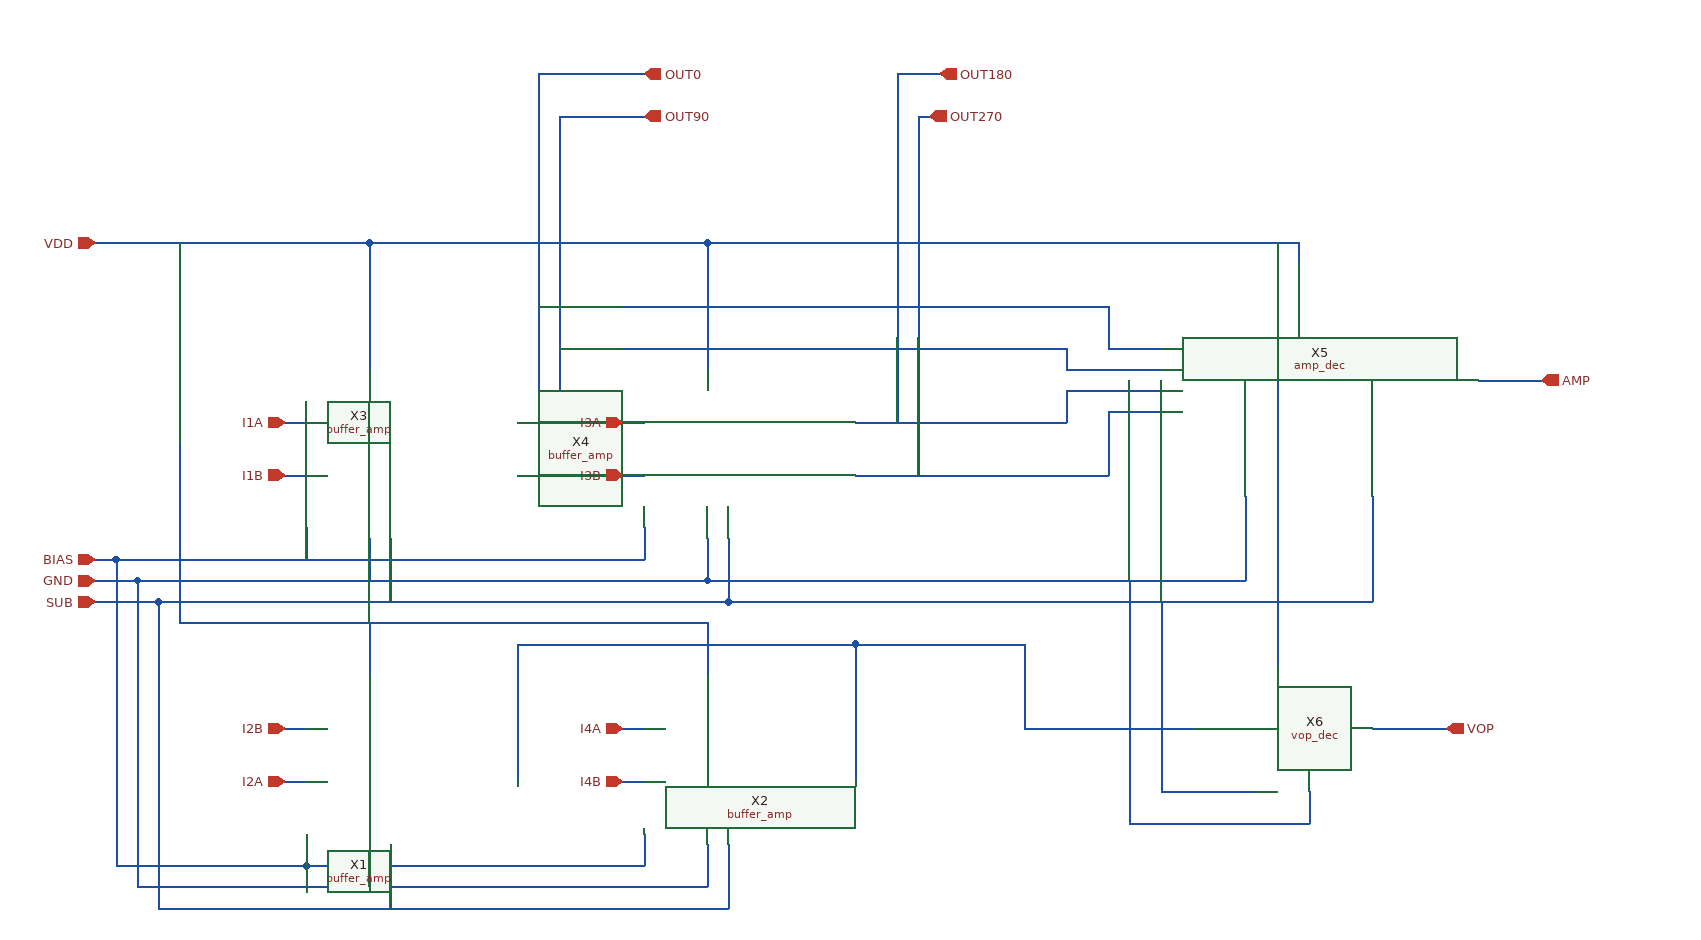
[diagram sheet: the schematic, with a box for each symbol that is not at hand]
v {xschem version=3.0.0 file_version=1.2 }
G {}
K {}
V {}
S {}
E {}
N 400 -280 400 -220 {
lab=SUB}
N -80 -220 400 -220 {
lab=SUB}
N 380 -280 380 -240 {
lab=GND}
N -80 -240 380 -240 {
lab=GND}
N 320 -290 320 -260 {
lab=BIAS}
N -70 -260 320 -260 {
lab=BIAS}
N -200 -260 -190 -260 {
lab=BIAS}
N -0 -290 -0 -260 {
lab=BIAS}
N 60 -280 60 -240 {
lab=GND}
N 80 -280 80 -220 {
lab=SUB}
N 400 10 400 70 {
lab=SUB}
N 380 10 380 50 {
lab=GND}
N 320 0 320 30 {
lab=BIAS}
N 0 0 0 30 {
lab=BIAS}
N 60 10 60 50 {
lab=GND}
N 80 10 80 70 {
lab=SUB}
N -180 -260 -180 20 {
lab=BIAS}
N -180 20 -180 30 {
lab=BIAS}
N -160 -240 -160 50 {
lab=GND}
N -140 -220 -140 70 {
lab=SUB}
N -60 30 0 30 {
lab=BIAS}
N 0 30 320 30 {
lab=BIAS}
N -40 50 380 50 {
lab=GND}
N -20 70 400 70 {
lab=SUB}
N -20 -340 -0 -340 {
lab=I1B}
N -20 -390 0 -390 {
lab=I1A}
N 300 -390 320 -390 {
lab=I3A}
N 300 -340 320 -340 {
lab=I3B}
N -180 30 -60 30 {
lab=BIAS}
N -160 50 -40 50 {
lab=GND}
N -140 70 -20 70 {
lab=SUB}
N -140 -220 -80 -220 {
lab=SUB}
N -160 -240 -80 -240 {
lab=GND}
N -180 -260 -70 -260 {
lab=BIAS}
N -190 -260 -180 -260 {
lab=BIAS}
N -200 -240 -160 -240 {
lab=GND}
N -200 -220 -140 -220 {
lab=SUB}
N -20 -100 0 -100 {
lab=I2B}
N -20 -50 -0 -50 {
lab=I2A}
N 200 -100 200 -50 {
lab=#net1}
N 300 -100 320 -100 {
lab=I4A}
N 300 -50 320 -50 {
lab=I4B}
N 520 -100 520 -50 {
lab=#net1}
N 60 -560 380 -560 {
lab=VDD}
N -200 -560 60 -560 {
lab=VDD}
N 200 -130 200 -100 {
lab=#net1}
N 380 -200 380 -150 {
lab=VDD}
N -120 -200 380 -200 {
lab=VDD}
N -120 -440 -120 -200 {
lab=VDD}
N 60 -200 60 -150 {
lab=VDD}
N 200 -180 200 -130 {
lab=#net1}
N 200 -180 520 -180 {
lab=#net1}
N 520 -180 520 -100 {
lab=#net1}
N 520 -180 680 -180 {
lab=#net1}
N 520 -340 680 -340 {
lab=OUT270}
N 520 -390 680 -390 {
lab=OUT180}
N 200 -390 220 -390 {
lab=OUT0}
N 220 -600 220 -390 {
lab=OUT0}
N 200 -340 240 -340 {
lab=OUT90}
N 240 -600 240 -340 {
lab=OUT90}
N 560 -600 560 -390 {
lab=OUT180}
N 580 -600 580 -340 {
lab=OUT270}
N -120 -560 -120 -440 {
lab=VDD}
N 220 -500 680 -500 {
lab=OUT0}
N 380 -560 380 -440 {
lab=VDD}
N 240 -460 670 -460 {
lab=OUT90}
N 380 -240 890 -240 {
lab=GND}
N 890 -320 890 -240 {
lab=GND}
N 400 -220 1010 -220 {
lab=SUB}
N 1010 -320 1010 -220 {
lab=SUB}
N 760 -460 810 -460 {
lab=OUT0}
N 760 -500 760 -460 {
lab=OUT0}
N 680 -500 760 -500 {
lab=OUT0}
N 720 -440 810 -440 {
lab=OUT90}
N 720 -460 720 -440 {
lab=OUT90}
N 670 -460 720 -460 {
lab=OUT90}
N 680 -340 760 -340 {
lab=OUT270}
N 760 -400 760 -340 {
lab=OUT270}
N 760 -400 810 -400 {
lab=OUT270}
N 680 -390 720 -390 {
lab=OUT180}
N 720 -420 720 -390 {
lab=OUT180}
N 720 -420 810 -420 {
lab=OUT180}
N 220 -720 320 -720 {
lab=OUT0}
N 220 -720 220 -600 {
lab=OUT0}
N 240 -680 320 -680 {
lab=OUT90}
N 240 -680 240 -600 {
lab=OUT90}
N 560 -720 560 -600 {
lab=OUT180}
N 560 -720 600 -720 {
lab=OUT180}
N 580 -680 580 -600 {
lab=OUT270}
N 580 -680 590 -680 {
lab=OUT270}
N 380 -560 940 -560 {
lab=VDD}
N 940 -560 940 -540 {
lab=VDD}
N 680 -180 680 -100 {
lab=#net1}
N 680 -100 840 -100 {
lab=#net1}
N 1110 -430 1170 -430 {
lab=AMP}
N 1010 -100 1080 -100 {
lab=VOP}
N 60 -560 60 -440 {
lab=VDD}
N 920 -560 920 -160 {
lab=VDD}
N 810 -40 900 -40 {
lab=SUB}
N 810 -220 810 -40 {
lab=SUB}
N 950 -40 950 -10 {
lab=GND}
N 780 -10 950 -10 {
lab=GND}
N 780 -240 780 -10 {
lab=GND}
C {hiarachy_final/buffer_amp.sym} 0 -20 0 0 {name=X1}
C {hiarachy_final/buffer_amp.sym} 320 -20 0 0 {name=X2}
C {hiarachy_final/buffer_amp.sym} 0 -310 0 0 {name=X3}
C {hiarachy_final/buffer_amp.sym} 320 -310 0 0 {name=X4}
C {ipin.sym} -200 -260 0 0 {name=p2 lab=BIAS}
C {ipin.sym} -200 -240 0 0 {name=p3 lab=GND}
C {ipin.sym} -200 -220 0 0 {name=p4 lab=SUB}
C {ipin.sym} -20 -390 0 0 {name=p5 lab=I1A}
C {ipin.sym} -20 -340 0 0 {name=p6 lab=I1B}
C {ipin.sym} -20 -50 0 0 {name=p7 lab=I2A}
C {ipin.sym} -20 -100 0 0 {name=p8 lab=I2B}
C {ipin.sym} 300 -390 0 0 {name=p9 lab=I3A}
C {ipin.sym} 300 -340 0 0 {name=p10 lab=I3B}
C {ipin.sym} 300 -100 0 0 {name=p11 lab=I4A}
C {ipin.sym} 300 -50 0 0 {name=p12 lab=I4B}
C {ipin.sym} -200 -560 0 0 {name=p1 lab=VDD}
C {hiarachy_final/amp_dec.sym} 770 -300 0 0 {name=X5}
C {hiarachy_final/vop_dec.sym} 840 -50 0 0 {name=X6}
C {opin.sym} 1170 -430 0 0 {name=p17 lab=AMP}
C {opin.sym} 1080 -100 0 0 {name=p18 lab=VOP}
C {opin.sym} 320 -720 0 0 {name=p13 lab=OUT0}
C {opin.sym} 320 -680 0 0 {name=p14 lab=OUT90}
C {opin.sym} 600 -720 0 0 {name=p15 lab=OUT180}
C {opin.sym} 590 -680 0 0 {name=p16 lab=OUT270}
